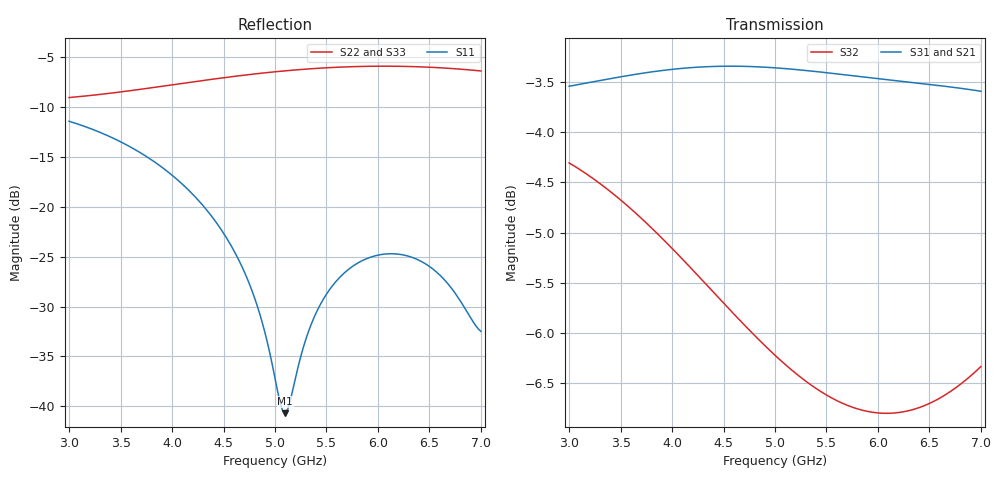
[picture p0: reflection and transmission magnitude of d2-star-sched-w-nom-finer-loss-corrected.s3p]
! yapnr Order 0 prediction d2-star-sched-w-nom-finer: predictions/D2/variants/d2-star-sched-w-nom/finer.s3p, loss-corrected
! substrate W-nom; coupon model OSHPARK-4L-FR408HR; correction: ratio (port line)
! |S21|, |S31| (and S12, S13) scaled, phases kept; 50 ohm, e^(+jwt)
# GHz S RI R 50
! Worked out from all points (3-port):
!   161 points, 3 GHz to 7 GHz, reference 50 ohm
!   strongest paths, dB at 3 GHz, 4 GHz, 5 GHz, 6 GHz, 7 GHz:
!     S31: -3.5, -3.4, -3.4, -3.5, -3.6
!     S21: -3.5, -3.4, -3.4, -3.5, -3.6
!     S32: -4.3, -5.2, -6.2, -6.8, -6.3
!   lowest |S11| = -40.7 dB at 5.1 GHz (marker M1), VSWR 1.02, Z = 49.5 + j0.796 ohm
!   |S11| at or under -10 dB: start of sweep to end of sweep
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3  -0.0904 0.2534  -0.3621 -0.5584  -0.3621 -0.5584
   -0.3621 -0.5579  0.3095 0.1715  -0.577 -0.195
   -0.3621 -0.5579  -0.577 -0.195  0.3095 0.1715
3.6  0.00504 0.1993  -0.5781 -0.3463  -0.5781 -0.3463
     -0.5778 -0.3463  0.3799 -0.0518  -0.5609 0.1388
     -0.5778 -0.3463  -0.5609 0.1388  0.3799 -0.0518
4.35  0.0441 0.0837  -0.6788 0.0336  -0.6788 0.0336
      -0.6794 0.0324  0.2808 -0.3314  -0.3195 0.4212
      -0.6794 0.0324  -0.3195 0.4212  0.2808 -0.3314
4.75  0.0245 0.0332  -0.6334 0.2448  -0.6334 0.2448
      -0.6352 0.2437  0.1568 -0.434  -0.1523 0.4792
      -0.6352 0.2437  -0.1523 0.4792  0.1568 -0.434
5  0.00421 0.0132  -0.5707 0.3651  -0.5707 0.3651
   -0.5732 0.3646  0.0637 -0.4722  -0.0501 0.4859
   -0.5732 0.3646  -0.0501 0.4859  0.0637 -0.4722
5.1  -0.00453 0.00803  -0.539 0.4091  -0.539 0.4091
     -0.5416 0.4089  0.0245 -0.4813  -0.0108 0.4832
     -0.5416 0.4089  -0.0108 0.4832  0.0245 -0.4813
5.425  -0.0312 0.00181  -0.4133 0.5317  -0.4133 0.5317
       -0.4163 0.5328  -0.1051 -0.4852  0.108 0.4567
       -0.4163 0.5328  0.108 0.4567  -0.1051 -0.4852
5.875  -0.0533 0.0118  -0.197 0.639  -0.197 0.639
       -0.199 0.6419  -0.2725 -0.428  0.2483 0.3852
       -0.199 0.6419  0.2483 0.3852  -0.2725 -0.428
6.475  -0.0453 0.0241  0.1236 0.6515  0.1236 0.6515
       0.1249 0.6548  -0.4296 -0.2617  0.3929 0.2424
       0.1249 0.6548  0.3929 0.2424  -0.4296 -0.2617
7  -0.0237 -0.00108  0.3842 0.5348  0.3842 0.5348
   0.3876 0.5357  -0.475 -0.0752  0.4765 0.0738
   0.3876 0.5357  0.4765 0.0738  -0.475 -0.0752
